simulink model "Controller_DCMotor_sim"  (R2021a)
settings: Solver=FixedStepAuto  StartTime=0.0  StopTime=inf  FixedStep=0.05  RelTol=1e-3  EnableMultiTasking=on
libraries: arduinolib x7

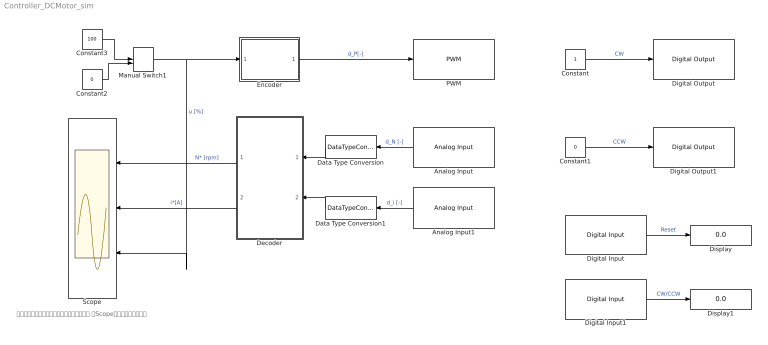
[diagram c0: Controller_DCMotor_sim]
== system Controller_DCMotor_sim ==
  note: シミュレーション結果が表示されない場合は 「Scope」をダブルクリック
  Analog Input : arduinolib/Analog Input  pinNumber=5  ReadResultsOnly=off  ConversionTriggerSource=Software  ExternalTriggerType=uint32( 0 )  OutputDataType=uint16  EnableConversionCompleteNotify=off  EnableOuputStatus=off  SampleTime=-1  blockPlatform=arduino
  Analog Input1 : arduinolib/Analog Input  pinNumber=8  ReadResultsOnly=off  ConversionTriggerSource=Software  ExternalTriggerType=uint32( 0 )  OutputDataType=uint16  EnableConversionCompleteNotify=off  EnableOuputStatus=off  SampleTime=-1  blockPlatform=arduino
  Constant : Constant
  Constant1 : Constant  Value=0
  Constant2 : Constant  Value=0
  Constant3 : Constant  Value=100
  Data Type Conversion : DataTypeConversion
  Data Type Conversion1 : DataTypeConversion
  Decoder : Subsystem
  Digital Input : arduinolib/Digital Input  pinNumber=3  mode=Default  Direction=input  SampleTime=-1  blockPlatform=arduino
  Digital Input1 : arduinolib/Digital Input  pinNumber=5  mode=Default  Direction=input  SampleTime=-1  blockPlatform=arduino
  Digital Output : arduinolib/Digital Output  pinNumber=8  Direction=output  blockPlatform=arduino
  Digital Output1 : arduinolib/Digital Output  pinNumber=7  Direction=output  blockPlatform=arduino
  Display : Display
  Display1 : Display
  Encoder : Subsystem
  Manual Switch1 : ManualSwitch  CurrentSetting=0
  PWM : arduinolib/PWM  pinNumber=10  frequencyType=Default  desiredFrequency=490.2  achievableFrequency=490.2
  Scope : Scope  NumInputPorts=3
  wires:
  Encoder/1(d_P [-]) -> PWM/1  "d_P[-]"
  Constant1/1 -> Digital Output1/1  "CCW"
  Constant/1 -> Digital Output/1  "CW"
  Manual Switch1/1 -> Scope/3, Encoder/1(u [%])  "u [%]"
  Constant3/1 -> Manual Switch1/1
  Constant2/1 -> Manual Switch1/2
  Decoder/2(i* [A]) -> Scope/2  "i*[A]"
  Decoder/1(N* [rpm]) -> Scope/1  "N* [rpm]"
  Analog Input/1 -> Data Type Conversion/1  "d_N [-]"
  Analog Input1/1 -> Data Type Conversion1/1  "d_i [-]"
  Data Type Conversion/1 -> Decoder/1(d_N [-])
  Data Type Conversion1/1 -> Decoder/2(d_i [-])
  Digital Input/1 -> Display/1  "Reset"
  Digital Input1/1 -> Display1/1  "CW/CCW"

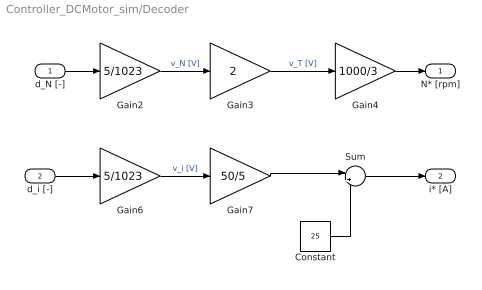
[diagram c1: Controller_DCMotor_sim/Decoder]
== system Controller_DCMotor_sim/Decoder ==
  d_N [-] : Inport
  d_i [-] : Inport  Port=2
  Constant : Constant  Value=25
  Gain2 : Gain  Gain=5/1023
  Gain3 : Gain  Gain=2
  Gain4 : Gain  Gain=1000/3
  Gain6 : Gain  Gain=5/1023
  Gain7 : Gain  Gain=50/5
  Sum : Sum  Inputs=|+-
  N* [rpm] : Outport
  i* [A] : Outport  Port=2
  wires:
  Gain2/1 -> Gain3/1  "v_N [V]"
  d_N [-]/1 -> Gain2/1
  d_i [-]/1 -> Gain6/1
  Gain3/1 -> Gain4/1  "v_T [V]"
  Gain4/1 -> N* [rpm]/1
  Gain7/1 -> Sum/1
  Gain6/1 -> Gain7/1  "v_i [V]"
  Sum/1 -> i* [A]/1
  Constant/1 -> Sum/2

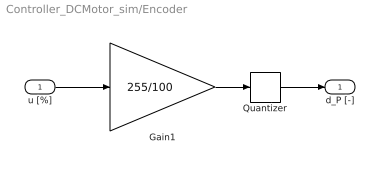
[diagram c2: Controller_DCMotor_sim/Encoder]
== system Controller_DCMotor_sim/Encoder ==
  u [%] : Inport
  Gain1 : Gain  Gain=255/100
  Quantizer : Quantizer
  d_P [-] : Outport
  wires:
  Gain1/1 -> Quantizer/1
  Quantizer/1 -> d_P [-]/1
  u [%]/1 -> Gain1/1
